VERSION 5.8 ;
BUSBITCHARS "[]" ;
DIVIDERCHAR "/" ;
UNITS
    DATABASE MICRONS 1000 ;
END UNITS

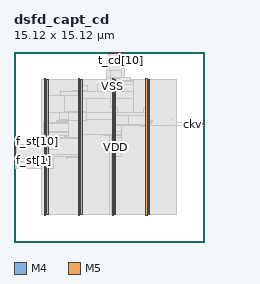
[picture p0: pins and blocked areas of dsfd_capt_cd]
MACRO dsfd_capt_cd
  FOREIGN dsfd_capt_cd 0 0 ;
  CLASS BLOCK ;
  SIZE 15.12 BY 15.12 ;
  PIN ckv
    DIRECTION INPUT ;
    USE SIGNAL ;
    PORT
      LAYER M4 ;
        RECT  15.036 9.36 15.12 9.384 ;
    END
  END ckv
  PIN f_st[0]
    DIRECTION INPUT ;
    USE SIGNAL ;
    PORT
      LAYER M4 ;
        RECT  0 6.384 0.084 6.408 ;
    END
  END f_st[0]
  PIN f_st[10]
    DIRECTION INPUT ;
    USE SIGNAL ;
    PORT
      LAYER M4 ;
        RECT  0 7.344 0.084 7.368 ;
    END
  END f_st[10]
  PIN f_st[11]
    DIRECTION INPUT ;
    USE SIGNAL ;
    PORT
      LAYER M4 ;
        RECT  0 7.44 0.084 7.464 ;
    END
  END f_st[11]
  PIN f_st[12]
    DIRECTION INPUT ;
    USE SIGNAL ;
    PORT
      LAYER M4 ;
        RECT  0 7.536 0.084 7.56 ;
    END
  END f_st[12]
  PIN f_st[13]
    DIRECTION INPUT ;
    USE SIGNAL ;
    PORT
      LAYER M4 ;
        RECT  0 7.632 0.084 7.656 ;
    END
  END f_st[13]
  PIN f_st[1]
    DIRECTION INPUT ;
    USE SIGNAL ;
    PORT
      LAYER M4 ;
        RECT  0 6.48 0.084 6.504 ;
    END
  END f_st[1]
  PIN f_st[2]
    DIRECTION INPUT ;
    USE SIGNAL ;
    PORT
      LAYER M4 ;
        RECT  0 6.576 0.084 6.6 ;
    END
  END f_st[2]
  PIN f_st[3]
    DIRECTION INPUT ;
    USE SIGNAL ;
    PORT
      LAYER M4 ;
        RECT  0 6.672 0.084 6.696 ;
    END
  END f_st[3]
  PIN f_st[4]
    DIRECTION INPUT ;
    USE SIGNAL ;
    PORT
      LAYER M4 ;
        RECT  0 6.768 0.084 6.792 ;
    END
  END f_st[4]
  PIN f_st[5]
    DIRECTION INPUT ;
    USE SIGNAL ;
    PORT
      LAYER M4 ;
        RECT  0 6.864 0.084 6.888 ;
    END
  END f_st[5]
  PIN f_st[6]
    DIRECTION INPUT ;
    USE SIGNAL ;
    PORT
      LAYER M4 ;
        RECT  0 6.96 0.084 6.984 ;
    END
  END f_st[6]
  PIN f_st[7]
    DIRECTION INPUT ;
    USE SIGNAL ;
    PORT
      LAYER M4 ;
        RECT  0 7.056 0.084 7.08 ;
    END
  END f_st[7]
  PIN f_st[8]
    DIRECTION INPUT ;
    USE SIGNAL ;
    PORT
      LAYER M4 ;
        RECT  0 7.152 0.084 7.176 ;
    END
  END f_st[8]
  PIN f_st[9]
    DIRECTION INPUT ;
    USE SIGNAL ;
    PORT
      LAYER M4 ;
        RECT  0 7.248 0.084 7.272 ;
    END
  END f_st[9]
  PIN rsv
    DIRECTION INPUT ;
    USE SIGNAL ;
    PORT
      LAYER M4 ;
        RECT  15.036 9.456 15.12 9.48 ;
    END
  END rsv
  PIN t_cd[0]
    DIRECTION OUTPUT ;
    USE SIGNAL ;
    PORT
      LAYER M5 ;
        RECT  7.536 15.036 7.56 15.12 ;
    END
  END t_cd[0]
  PIN t_cd[10]
    DIRECTION OUTPUT ;
    USE SIGNAL ;
    PORT
      LAYER M5 ;
        RECT  8.496 15.036 8.52 15.12 ;
    END
  END t_cd[10]
  PIN t_cd[11]
    DIRECTION OUTPUT ;
    USE SIGNAL ;
    PORT
      LAYER M5 ;
        RECT  8.592 15.036 8.616 15.12 ;
    END
  END t_cd[11]
  PIN t_cd[1]
    DIRECTION OUTPUT ;
    USE SIGNAL ;
    PORT
      LAYER M5 ;
        RECT  7.632 15.036 7.656 15.12 ;
    END
  END t_cd[1]
  PIN t_cd[2]
    DIRECTION OUTPUT ;
    USE SIGNAL ;
    PORT
      LAYER M5 ;
        RECT  7.728 15.036 7.752 15.12 ;
    END
  END t_cd[2]
  PIN t_cd[3]
    DIRECTION OUTPUT ;
    USE SIGNAL ;
    PORT
      LAYER M5 ;
        RECT  7.824 15.036 7.848 15.12 ;
    END
  END t_cd[3]
  PIN t_cd[4]
    DIRECTION OUTPUT ;
    USE SIGNAL ;
    PORT
      LAYER M5 ;
        RECT  7.92 15.036 7.944 15.12 ;
    END
  END t_cd[4]
  PIN t_cd[5]
    DIRECTION OUTPUT ;
    USE SIGNAL ;
    PORT
      LAYER M5 ;
        RECT  8.016 15.036 8.04 15.12 ;
    END
  END t_cd[5]
  PIN t_cd[6]
    DIRECTION OUTPUT ;
    USE SIGNAL ;
    PORT
      LAYER M5 ;
        RECT  8.112 15.036 8.136 15.12 ;
    END
  END t_cd[6]
  PIN t_cd[7]
    DIRECTION OUTPUT ;
    USE SIGNAL ;
    PORT
      LAYER M5 ;
        RECT  8.208 15.036 8.232 15.12 ;
    END
  END t_cd[7]
  PIN t_cd[8]
    DIRECTION OUTPUT ;
    USE SIGNAL ;
    PORT
      LAYER M5 ;
        RECT  8.304 15.036 8.328 15.12 ;
    END
  END t_cd[8]
  PIN t_cd[9]
    DIRECTION OUTPUT ;
    USE SIGNAL ;
    PORT
      LAYER M5 ;
        RECT  8.4 15.036 8.424 15.12 ;
    END
  END t_cd[9]
  PIN VDD
    DIRECTION INOUT ;
    USE POWER ;
    PORT
      LAYER M5 ;
        RECT  10.692 2.151 10.812 12.969 ;
        RECT  7.992 2.151 8.112 12.969 ;
        RECT  5.292 2.151 5.412 12.969 ;
        RECT  2.592 2.151 2.712 12.969 ;
    END
  END VDD
  PIN VSS
    DIRECTION INOUT ;
    USE GROUND ;
    PORT
      LAYER M5 ;
        RECT  10.5 2.137 10.62 12.983 ;
        RECT  7.8 2.137 7.92 12.983 ;
        RECT  5.1 2.137 5.22 12.983 ;
        RECT  2.4 2.137 2.52 12.983 ;
    END
  END VSS
  # OT_OBS_CLOSED layer=M5 d_um=1.536 added=3
  OBS
    LAYER RVTN ;
     RECT  2.16 2.16 12.96 2.295 ;
     RECT  2.16 2.565 12.96 2.835 ;
     RECT  2.16 3.105 12.96 3.375 ;
     RECT  2.16 3.645 12.96 3.915 ;
     RECT  2.16 4.185 12.96 4.455 ;
     RECT  2.16 4.725 12.96 4.995 ;
     RECT  2.16 5.265 12.96 5.535 ;
     RECT  2.16 5.805 12.96 6.075 ;
     RECT  2.16 6.345 12.96 6.615 ;
     RECT  2.16 6.885 12.96 7.155 ;
     RECT  2.16 7.425 12.96 7.695 ;
     RECT  2.16 7.965 12.96 8.235 ;
     RECT  2.16 8.505 12.96 8.775 ;
     RECT  2.16 9.045 12.96 9.315 ;
     RECT  2.16 9.585 12.96 9.855 ;
     RECT  2.16 10.125 12.96 10.395 ;
     RECT  2.16 10.665 12.96 10.935 ;
     RECT  2.16 11.205 12.96 11.475 ;
     RECT  2.16 11.745 12.96 12.015 ;
     RECT  2.16 12.285 12.96 12.555 ;
     RECT  2.16 12.825 12.96 12.96 ;
    LAYER RVTP ;
     RECT  2.16 2.295 12.96 2.565 ;
     RECT  2.16 2.835 12.96 3.105 ;
     RECT  2.16 3.375 12.96 3.645 ;
     RECT  2.16 3.915 12.96 4.185 ;
     RECT  2.16 4.455 12.96 4.725 ;
     RECT  2.16 4.995 12.96 5.265 ;
     RECT  2.16 5.535 12.96 5.805 ;
     RECT  2.16 6.075 12.96 6.345 ;
     RECT  2.16 6.615 12.96 6.885 ;
     RECT  2.16 7.155 12.96 7.425 ;
     RECT  2.16 7.695 12.96 7.965 ;
     RECT  2.16 8.235 12.96 8.505 ;
     RECT  2.16 8.775 12.96 9.045 ;
     RECT  2.16 9.315 12.96 9.585 ;
     RECT  2.16 9.855 12.96 10.125 ;
     RECT  2.16 10.395 12.96 10.665 ;
     RECT  2.16 10.935 12.96 11.205 ;
     RECT  2.16 11.475 12.96 11.745 ;
     RECT  2.16 12.015 12.96 12.285 ;
     RECT  2.16 12.555 12.96 12.825 ;
    LAYER M1 ;
     RECT  2.16 2.151 12.96 12.969 ;
    LAYER M2 ;
     RECT  0.103 5.85 0.139 5.868 ;
     RECT  0.139 5.85 0.175 6.138 ;
     RECT  0.175 5.85 2.16 6.408 ;
     RECT  2.16 2.151 7.627 12.969 ;
     RECT  7.627 2.151 7.727 13.014 ;
     RECT  7.727 2.151 12.96 12.969 ;
     RECT  12.96 9.522 14.243 9.54 ;
    LAYER M3 ;
     RECT  2.415 2.143 2.505 2.413 ;
     RECT  5.115 2.143 5.205 2.413 ;
     RECT  7.815 2.143 7.905 2.413 ;
     RECT  10.515 2.143 10.605 2.413 ;
     RECT  2.415 2.413 2.697 5.881 ;
     RECT  0.108 5.845 0.126 6.115 ;
     RECT  2.415 5.881 3.114 6.151 ;
     RECT  0.108 6.115 0.162 6.385 ;
     RECT  0.108 6.385 0.198 6.413 ;
     RECT  0.144 6.413 0.198 6.605 ;
     RECT  2.376 6.151 3.114 6.655 ;
     RECT  4.176 6.619 4.194 6.655 ;
     RECT  4.176 6.655 4.23 6.691 ;
     RECT  5.115 2.413 5.397 6.691 ;
     RECT  2.304 6.655 3.258 6.781 ;
     RECT  4.176 6.691 5.397 6.781 ;
     RECT  7.815 2.413 8.097 6.817 ;
     RECT  0.18 6.605 0.198 6.893 ;
     RECT  2.304 6.781 5.397 6.952 ;
     RECT  0.324 7.531 0.342 7.627 ;
     RECT  0.108 7.627 0.342 7.661 ;
     RECT  0.108 7.661 0.126 7.757 ;
     RECT  7.815 6.817 8.586 8.311 ;
     RECT  2.268 6.952 5.397 8.465 ;
     RECT  7.776 8.311 8.586 8.473 ;
     RECT  7.452 8.473 8.586 8.509 ;
     RECT  7.092 8.509 8.586 8.539 ;
     RECT  2.304 8.465 5.397 8.735 ;
     RECT  6.3 8.539 8.586 8.779 ;
     RECT  2.34 8.735 5.397 8.815 ;
     RECT  6.228 8.779 8.586 8.815 ;
     RECT  10.515 2.413 10.797 9.211 ;
     RECT  10.08 9.211 10.797 9.319 ;
     RECT  10.044 9.319 10.797 9.355 ;
     RECT  15.012 9.259 15.03 9.389 ;
     RECT  2.34 8.815 8.586 9.391 ;
     RECT  9.648 9.355 10.797 9.391 ;
     RECT  2.34 9.391 10.926 9.545 ;
     RECT  14.22 9.451 14.238 9.545 ;
     RECT  3.42 9.545 10.926 9.589 ;
     RECT  3.42 9.589 10.998 9.653 ;
     RECT  3.6 9.653 10.998 9.689 ;
     RECT  3.6 9.689 10.854 9.779 ;
     RECT  12.6 9.661 12.618 9.815 ;
     RECT  3.6 9.779 10.797 10.319 ;
     RECT  10.296 10.319 10.797 10.589 ;
     RECT  10.404 10.589 10.797 10.733 ;
     RECT  3.6 10.319 9.486 11.399 ;
     RECT  3.672 11.399 9.486 11.939 ;
     RECT  4.536 11.939 9.486 12.011 ;
     RECT  3.672 11.939 3.69 12.083 ;
     RECT  4.536 12.011 5.85 12.083 ;
     RECT  5.115 12.083 5.85 12.479 ;
     RECT  6.66 12.011 9.486 12.551 ;
     RECT  2.415 9.545 2.697 12.707 ;
     RECT  5.115 12.479 5.397 12.707 ;
     RECT  10.515 10.733 10.797 12.707 ;
     RECT  7.272 12.551 9.486 12.785 ;
     RECT  7.38 12.785 9.486 12.857 ;
     RECT  2.415 12.707 2.505 12.977 ;
     RECT  5.115 12.707 5.205 12.977 ;
     RECT  10.515 12.707 10.605 12.977 ;
     RECT  7.38 12.857 9.234 13.085 ;
     RECT  7.38 13.085 8.766 14.237 ;
     RECT  7.38 14.237 8.622 14.285 ;
     RECT  7.74 14.285 8.622 14.717 ;
     RECT  7.74 14.717 8.37 15.005 ;
    LAYER M4 ;
     RECT  0.06 6.384 0.097 7.656 ;
     RECT  0.097 6.384 0.137 7.752 ;
     RECT  0.137 6.576 0.173 7.752 ;
     RECT  0.173 6.672 2.408 7.752 ;
     RECT  2.408 2.148 2.512 12.972 ;
     RECT  2.512 2.418 2.704 12.702 ;
     RECT  2.704 7.152 2.765 8.28 ;
     RECT  2.765 7.392 3.443 8.28 ;
     RECT  2.704 11.616 4.019 11.64 ;
     RECT  3.443 8.256 4.057 8.28 ;
     RECT  4.057 8.256 4.357 8.424 ;
     RECT  4.357 8.256 5.108 9.288 ;
     RECT  3.973 10.32 5.108 10.344 ;
     RECT  5.108 2.148 5.212 12.972 ;
     RECT  5.212 2.418 5.404 12.702 ;
     RECT  5.404 10.704 5.747 11.448 ;
     RECT  5.747 11.424 6.149 11.448 ;
     RECT  7.369 14.256 7.621 14.28 ;
     RECT  7.621 13.632 7.669 14.28 ;
     RECT  7.669 13.632 7.685 14.904 ;
     RECT  5.404 8.544 7.808 9.72 ;
     RECT  7.669 10.704 7.808 10.728 ;
     RECT  7.685 13.632 7.808 15 ;
     RECT  7.808 2.148 7.912 15 ;
     RECT  7.912 2.418 8.104 15 ;
     RECT  8.104 9.264 8.237 10.728 ;
     RECT  8.104 13.056 8.273 15 ;
     RECT  8.273 14.208 8.381 15 ;
     RECT  8.273 13.056 8.531 13.128 ;
     RECT  8.381 14.208 8.633 14.712 ;
     RECT  8.633 14.208 8.777 14.232 ;
     RECT  8.237 9.264 9.137 10.056 ;
     RECT  8.531 13.056 9.245 13.08 ;
     RECT  9.137 9.264 10.508 9.672 ;
     RECT  10.508 2.148 10.612 12.972 ;
     RECT  10.612 2.418 10.804 12.702 ;
     RECT  10.804 9.264 14.209 9.288 ;
     RECT  14.209 9.264 15.041 9.48 ;
     RECT  15.041 9.36 15.084 9.48 ;
    LAYER M5 ;
     RECT  2.4 2.137 2.52 2.151 ;
     RECT  5.1 2.137 5.22 2.151 ;
     RECT  7.8 2.137 7.92 2.151 ;
     RECT  10.5 2.137 10.62 2.151 ;
     RECT  2.4 2.151 2.712 7.381 ;
     RECT  2.4 7.381 3.432 8.245 ;
     RECT  5.1 2.151 5.412 8.245 ;
     RECT  2.4 8.245 5.412 8.291 ;
     RECT  7.8 2.151 8.112 9.349 ;
     RECT  4.368 8.291 5.412 9.637 ;
     RECT  7.8 9.349 9.096 10.067 ;
     RECT  4.368 9.637 5.736 10.309 ;
     RECT  3.984 10.309 5.736 10.355 ;
     RECT  7.8 10.067 8.112 10.693 ;
     RECT  5.1 10.355 5.736 11.459 ;
     RECT  3.984 10.355 4.008 11.651 ;
     RECT  2.4 8.291 2.712 12.969 ;
     RECT  5.1 11.459 5.412 12.969 ;
     RECT  10.5 2.151 10.812 12.969 ;
     RECT  2.4 12.969 2.52 12.983 ;
     RECT  5.1 12.969 5.22 12.983 ;
     RECT  10.5 12.969 10.62 12.983 ;
     RECT  7.68 10.693 8.112 13.045 ;
     RECT  7.68 13.045 8.424 13.093 ;
     RECT  7.68 13.093 8.52 13.621 ;
     RECT  7.632 13.621 8.52 14.197 ;
     RECT  7.632 14.197 8.616 14.245 ;
     RECT  7.536 14.245 8.616 15.056 ;
     RECT  9.096 9.349 10.5 10.067 ;
     RECT  2.712 10.309 3.984 11.651 ;
     RECT  4.008 10.355 5.1 11.651 ;
  END
END dsfd_capt_cd
END LIBRARY
